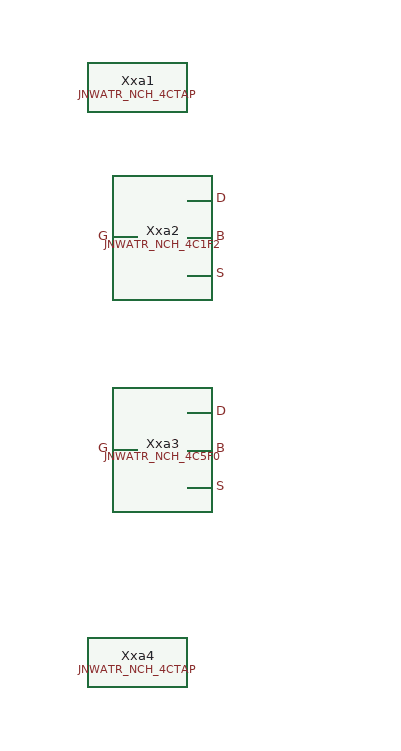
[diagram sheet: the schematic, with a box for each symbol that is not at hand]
v {xschem version=3.0.0 file_version=1.2 }
G {}
K {}
V {}
S {}
E {}
C {JNW_ATR_SKY130A/JNWATR_NCH_4CTAP.sym} 400 0 0 0 {name=Xxa1}
C {JNW_ATR_SKY130A/JNWATR_NCH_4C1F2.sym} 400 120.0 0 0 {name=Xxa2}
N 460.0 90.0 440.0 90.0 {lab=D}
C {devices/lab_pin.sym} 460.0 90.0 2 0 {name=l0 sig_type=std_logic lab=D }
N 380.0 120.0 400.0 120.0 {lab=G}
C {devices/lab_pin.sym} 380.0 120.0 0 0 {name=l1 sig_type=std_logic lab=G }
N 460.0 150.0 440.0 150.0 {lab=S}
C {devices/lab_pin.sym} 460.0 150.0 2 0 {name=l2 sig_type=std_logic lab=S }
N 460.0 120.0 440.0 120.0 {lab=B}
C {devices/lab_pin.sym} 460.0 120.0 2 0 {name=l3 sig_type=std_logic lab=B }
C {JNW_ATR_SKY130A/JNWATR_NCH_4C5F0.sym} 400 290.0 0 0 {name=Xxa3}
N 460.0 260.0 440.0 260.0 {lab=D}
C {devices/lab_pin.sym} 460.0 260.0 2 0 {name=l4 sig_type=std_logic lab=D }
N 380.0 290.0 400.0 290.0 {lab=G}
C {devices/lab_pin.sym} 380.0 290.0 0 0 {name=l5 sig_type=std_logic lab=G }
N 460.0 320.0 440.0 320.0 {lab=S}
C {devices/lab_pin.sym} 460.0 320.0 2 0 {name=l6 sig_type=std_logic lab=S }
N 460.0 290.0 440.0 290.0 {lab=B}
C {devices/lab_pin.sym} 460.0 290.0 2 0 {name=l7 sig_type=std_logic lab=B }
C {JNW_ATR_SKY130A/JNWATR_NCH_4CTAP.sym} 400 460.0 0 0 {name=Xxa4}
